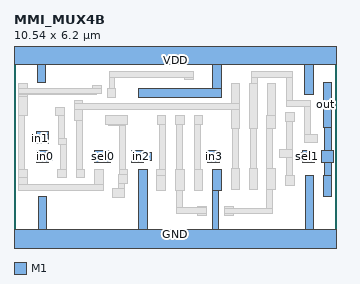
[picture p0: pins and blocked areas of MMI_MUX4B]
MACRO MMI_MUX4B
	CLASS CORE ;
	FOREIGN MMI_MUX4B 0 0 ;
	SIZE 10.54 BY 6.2 ;
	SYMMETRY X Y ;
	SITE CORE1 ;
	PIN out
		DIRECTION output ;
		USE SIGNAL ;
		PORT
			LAYER M1 ;
			RECT 10.095 3.745 10.375 5.215 ;
			LAYER M1 ;
			RECT 10.13 2.98 10.37 3.745 ;
			LAYER M1 ;
			RECT 10.04 2.6 10.42 2.98 ;
			LAYER M1 ;
			RECT 10.13 2.17 10.37 2.6 ;
			LAYER M1 ;
			RECT 10.095 1.47 10.375 2.17 ;
		END
		AntennaDiffArea 0.91245 ;
	END out
	PIN sel0
		DIRECTION input ;
		USE SIGNAL ;
		PORT
			LAYER M1 ;
			RECT 2.64 2.595 3.145 2.985 ;
		END
		AntennaGateArea 0.927 ;
	END sel0
	PIN in1
		DIRECTION input ;
		USE SIGNAL ;
		PORT
			LAYER M1 ;
			RECT 0.74 3.52 1.12 3.6 ;
			LAYER M1 ;
			RECT 0.555 3.24 1.12 3.52 ;
			LAYER M1 ;
			RECT 0.74 3.22 1.12 3.24 ;
		END
		AntennaGateArea 0.3465 ;
	END in1
	PIN GND
		DIRECTION inout ;
		USE GROUND ;
		PORT
			LAYER M1 ;
			RECT 0.79 0.42 1.07 1.49 ;
			LAYER M1 ;
			RECT 4.075 0.42 4.355 2.37 ;
			LAYER M1 ;
			RECT 6.475 1.67 6.755 2.37 ;
			LAYER M1 ;
			RECT 6.475 0.42 6.665 1.67 ;
			LAYER M1 ;
			RECT 9.505 0.42 9.785 2.17 ;
			LAYER M1 ;
			RECT 0 -0.42 10.54 0.42 ;
		END
	END GND
	PIN in2
		DIRECTION input ;
		USE SIGNAL ;
		PORT
			LAYER M1 ;
			RECT 3.84 2.93 4.22 2.98 ;
			LAYER M1 ;
			RECT 3.84 2.65 4.48 2.93 ;
			LAYER M1 ;
			RECT 3.84 2.6 4.22 2.65 ;
		END
		AntennaGateArea 0.3465 ;
	END in2
	PIN sel1
		DIRECTION input ;
		USE SIGNAL ;
		PORT
			LAYER M1 ;
			RECT 9.425 2.93 9.8 2.98 ;
			LAYER M1 ;
			RECT 9.305 2.65 9.8 2.93 ;
			LAYER M1 ;
			RECT 9.425 2.6 9.8 2.65 ;
		END
		AntennaGateArea 0.51975 ;
	END sel1
	PIN VDD
		DIRECTION inout ;
		USE POWER ;
		PORT
			LAYER M1 ;
			RECT 0 5.78 10.54 6.62 ;
			LAYER M1 ;
			RECT 0.755 5.22 1.035 5.78 ;
			LAYER M1 ;
			RECT 6.48 5 6.765 5.78 ;
			LAYER M1 ;
			RECT 4.065 4.715 6.765 5 ;
			LAYER M1 ;
			RECT 9.495 4.815 9.775 5.78 ;
		END
	END VDD
	PIN in3
		DIRECTION input ;
		USE SIGNAL ;
		PORT
			LAYER M1 ;
			RECT 6.325 2.93 6.7 2.98 ;
			LAYER M1 ;
			RECT 6.325 2.65 6.71 2.93 ;
			LAYER M1 ;
			RECT 6.325 2.6 6.7 2.65 ;
		END
		AntennaGateArea 0.3465 ;
	END in3
	PIN in0
		DIRECTION input ;
		USE SIGNAL ;
		PORT
			LAYER M1 ;
			RECT 0.74 2.93 1.12 2.98 ;
			LAYER M1 ;
			RECT 0.74 2.65 1.265 2.93 ;
			LAYER M1 ;
			RECT 0.74 2.6 1.12 2.65 ;
		END
		AntennaGateArea 0.3465 ;
	END in0
	OBS
		LAYER M1 ;
		RECT 5.575 5.55 5.855 5.58 ;
		LAYER M1 ;
		RECT 3.1 5.36 5.855 5.55 ;
		LAYER M1 ;
		RECT 0.16 5.02 0.44 5.175 ;
		LAYER M1 ;
		RECT 2.565 5.02 2.845 5.11 ;
		LAYER M1 ;
		RECT 0.16 4.83 2.845 5.02 ;
		LAYER M1 ;
		RECT 3.1 4.995 3.295 5.36 ;
		LAYER M1 ;
		RECT 5.575 5.3 5.855 5.36 ;
		LAYER M1 ;
		RECT 7.76 5.38 9.08 5.57 ;
		LAYER M1 ;
		RECT 7.76 5.18 7.955 5.38 ;
		LAYER M1 ;
		RECT 0.16 4.825 2.695 4.83 ;
		LAYER M1 ;
		RECT 0.16 4.755 0.44 4.825 ;
		LAYER M1 ;
		RECT 0.15 4.115 0.44 4.755 ;
		LAYER M1 ;
		RECT 3.045 4.715 3.325 4.995 ;
		LAYER M1 ;
		RECT 1.965 4.515 2.245 4.625 ;
		LAYER M1 ;
		RECT 7.085 4.515 7.365 5.18 ;
		LAYER M1 ;
		RECT 1.36 4.115 1.64 4.395 ;
		LAYER M1 ;
		RECT 0.15 2.37 0.345 4.115 ;
		LAYER M1 ;
		RECT 1.45 3.37 1.64 4.115 ;
		LAYER M1 ;
		RECT 1.965 4.325 7.365 4.515 ;
		LAYER M1 ;
		RECT 1.965 3.955 2.245 4.325 ;
		LAYER M1 ;
		RECT 1.45 3.175 1.705 3.37 ;
		LAYER M1 ;
		RECT 1.51 2.37 1.705 3.175 ;
		LAYER M1 ;
		RECT 0.15 2.11 0.44 2.37 ;
		LAYER M1 ;
		RECT 0.16 1.885 0.44 2.11 ;
		LAYER M1 ;
		RECT 1.425 2.09 1.705 2.37 ;
		LAYER M1 ;
		RECT 2.03 2.37 2.225 3.955 ;
		LAYER M1 ;
		RECT 2.985 3.845 3.71 4.125 ;
		LAYER M1 ;
		RECT 4.67 3.845 4.95 4.125 ;
		LAYER M1 ;
		RECT 5.275 3.845 5.555 4.125 ;
		LAYER M1 ;
		RECT 5.875 3.845 6.155 4.125 ;
		LAYER M1 ;
		RECT 2.985 3.84 3.64 3.845 ;
		LAYER M1 ;
		RECT 2.99 3.82 3.64 3.84 ;
		LAYER M1 ;
		RECT 3.075 3.815 3.64 3.82 ;
		LAYER M1 ;
		RECT 3.45 2.37 3.64 3.815 ;
		LAYER M1 ;
		RECT 4.755 2.37 4.95 3.845 ;
		LAYER M1 ;
		RECT 5.315 2.37 5.505 3.845 ;
		LAYER M1 ;
		RECT 5.905 2.37 6.1 3.845 ;
		LAYER M1 ;
		RECT 7.085 3.71 7.365 4.325 ;
		LAYER M1 ;
		RECT 7.675 3.71 7.955 5.18 ;
		LAYER M1 ;
		RECT 8.265 4.135 8.545 5.18 ;
		LAYER M1 ;
		RECT 8.885 4.61 9.08 5.38 ;
		LAYER M1 ;
		RECT 8.885 4.415 9.66 4.61 ;
		LAYER M1 ;
		RECT 8.25 3.71 8.545 4.135 ;
		LAYER M1 ;
		RECT 8.86 3.93 9.14 4.21 ;
		LAYER M1 ;
		RECT 7.125 2.41 7.32 3.71 ;
		LAYER M1 ;
		RECT 7.715 2.41 7.905 3.71 ;
		LAYER M1 ;
		RECT 8.25 2.41 8.445 3.71 ;
		LAYER M1 ;
		RECT 8.9 3.03 9.09 3.93 ;
		LAYER M1 ;
		RECT 9.47 3.52 9.66 4.415 ;
		LAYER M1 ;
		RECT 9.47 3.24 9.91 3.52 ;
		LAYER M1 ;
		RECT 8.65 2.75 9.09 3.03 ;
		LAYER M1 ;
		RECT 2.03 2.09 2.31 2.37 ;
		LAYER M1 ;
		RECT 2.625 1.885 2.905 2.37 ;
		LAYER M1 ;
		RECT 3.435 2.2 3.715 2.37 ;
		LAYER M1 ;
		RECT 0.16 1.69 2.905 1.885 ;
		LAYER M1 ;
		RECT 3.425 1.92 3.715 2.2 ;
		LAYER M1 ;
		RECT 3.425 1.745 3.62 1.92 ;
		LAYER M1 ;
		RECT 0.16 1.67 0.44 1.69 ;
		LAYER M1 ;
		RECT 2.625 1.67 2.905 1.69 ;
		LAYER M1 ;
		RECT 3.2 1.465 3.62 1.745 ;
		LAYER M1 ;
		RECT 3.265 1.46 3.62 1.465 ;
		LAYER M1 ;
		RECT 4.665 2.18 4.95 2.37 ;
		LAYER M1 ;
		RECT 4.665 1.67 4.945 2.18 ;
		LAYER M1 ;
		RECT 5.27 1.67 5.55 2.37 ;
		LAYER M1 ;
		RECT 5.885 1.67 6.165 2.37 ;
		LAYER M1 ;
		RECT 7.085 1.71 7.365 2.41 ;
		LAYER M1 ;
		RECT 7.675 1.71 7.955 2.41 ;
		LAYER M1 ;
		RECT 8.25 1.71 8.545 2.41 ;
		LAYER M1 ;
		RECT 8.9 2.17 9.09 2.75 ;
		LAYER M1 ;
		RECT 8.865 1.855 9.145 2.17 ;
		LAYER M1 ;
		RECT 5.3 1.115 5.495 1.67 ;
		LAYER M1 ;
		RECT 5.99 1.115 6.27 1.155 ;
		LAYER M1 ;
		RECT 5.3 0.92 6.27 1.115 ;
		LAYER M1 ;
		RECT 5.99 0.875 6.27 0.92 ;
		LAYER M1 ;
		RECT 6.875 1.105 7.155 1.155 ;
		LAYER M1 ;
		RECT 8.25 1.105 8.445 1.71 ;
		LAYER M1 ;
		RECT 6.875 0.915 8.445 1.105 ;
		LAYER M1 ;
		RECT 6.875 0.875 7.155 0.915 ;
	END
END MMI_MUX4B
